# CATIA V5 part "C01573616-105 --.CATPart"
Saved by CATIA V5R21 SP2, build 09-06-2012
Part number: C01573616-105
Revision: ---
Description: PROPRIETARY NOTICE (do not delete / modify)  ***************************************************************************************************  LA SOCIETE EN COMMANDITE  AIRBUS CANADA  ("AIRBUS CANADA")  PAR  L'INTERMEDIAIRE  DE  SES  DIVISIONS  ET/OU  FILIALES  CORPORATIVES,  FOURNIT  LES PRESENTES  INFORMATIONS  AU  GOUVERNEMENT  A  TITRE CONFIDENTIEL. CES  INFORMATIONS ONT UNE TENEUR CONFIDENTIELLE,  AVEC DROITS DE PROPRIETE,  ET NOUS LES CONSIDERONS  EXCLUS  DE   L'APPLICATION  DE  LA LOI SUR L'ACCES A L'INFORMATION  (CANADA),  LES  LOIS  SUR  L'ACCES  A  L'INFORMATION  EUROPEENNES,  LE FREEDOM OF INFORMATION ACT (ETATS-UNIS) ET D'AUTRES LOIS SEMBLABLES. ELLES  PEUVENT  AUSSI  CONSTITUER DES SECRETS INDUSTRIELS DE NOTRE SOCIETE OU DE TIERCES PARTIES. LA DIVULGATION  PUBLIQUE  DE CES  INFORMATIONS NUIRAIT A AIRBUS CANADA OU A DES TIERCES PARTIES.  CES INFORMATIONS PEUVENT EGALEMENT CONTENIR  DES DONNEES QUI SONT CONTROLEE PAR DES LOIS DE CONTROLE DES EXPORTATIONS DU CANADA, L’EUROPE OU LES  ETATS-  UNIS. TOUTE EXPORTATION OU REEXPORTATION DE DONNEES CONTROLEES SANS AUTORISATION EST STRICTEMENT INTERDITE.  TOUTE INTENTION DE LES DIVULGUER EN TOUT OU EN PARTIE DEVRA ETRE SIGNIFIEE A L'AVANCE ET PAR ECRIT AU VICE-  PRESIDENT, SERVICES JURIDIQUES ET CONFORMITE ET SECRETAIRE CORPORATIF D'AIRBUS CANADA.    AIRBUS CANADA LIMITED PARTNERSHIP  ("AIRBUS CANADA"),  BY ITS AFFILIATES AND/OR SUBSIDIARIES, PROVIDES THIS  INFORMATION TO THE GOVERNMENT IN CONFIDENCE. THIS IS PROPRIETARY CONFIDENTIAL INFORMATION WHICH WE CONSIDER  EXCLUDED  FROM  THE  APPLICATION OF THE ACCESS TO INFORMATION ACT (CANADA),  THE FREEDOM OF INFORMATION ACT  (U.S.A.),  THE ACCESS TO INFORMATION LAWS IN EUROPE, AND OTHER SIMILAR LEGISLATION. AND MAY ALSO CONSTITUTE  TRADE SECRETS OF OUR  COMPANY OR THIRD PARTIES.  PUBLIC  RELEASE  OF  THIS INFORMATION  WOULD BE HARMFUL TO  AIRBUS CANADA OR THIRD PARTIES.  THIS  INFORMATION  MAY  ALSO  CONTAIN DATA THAT IS CONTROLLED BY CANADIAN,  EUROPEAN, OR U.S.A. EXPORT CONTROL LAWS. ANY UNAUTHORIZED EXPORT OR RE-EXPORT OF ANY EXPORT CONTROLLED DATA  IS STRICTLY PROHIBITED  ANY INTENTION TO DISCLOSE SUCH INFORMATION,  OR  PART THEREOF,  MUST BE NOTIFIED IN  ADVANCE AND IN WRITING TO THE VICE PRESIDENT, LEGAL AND COMPLIANCE AND CORPORATE SECRETARY OF AIRBUS CANADA.        LES RENSEIGNEMENTS,  LES DONNEES  ET  DESSINS  TECHNIQUES  DIVULGUES  DANS  LES PRESENTES SONT LA PROPRIETE  EXCLUSIVE DE LA SOCIETE EN COMMANDITE AIRBUS CANADA ("AIRBUS CANADA") OU COMPORTENT DES DROITS DE PROPRIETE  APPARTENANT  A  AUTRUI ET NE PEUVENT ETRE DIVULGUES  A  QUICONQUE  NI  UTILISES PAR QUI QUE CE SOIT SANS LE  CONSENTEMENT  ECRIT  D’AIRBUS  CANADA.  LE DETENTEUR DES  PRESENTES  S'ENGAGE, DANS TOUTES CIRCONSTANCES, A  GARDER CONFIDENTIELS LES DONNEES ET DESSINS TECHNIQUES QU'ELLES CONTIENNENT.   CE QUI PRECEDE NE S'APPLIQUE  PAS  AUX PERSONNES  QUI  ONT DES DROITS DE PROPRIETE SUR CES RENSEIGNEMENTS,  DONNEES TECHNIQUES ET DESSINS  DANS LA MESURE OU CES DROITS EXISTENT.    THE INFORMATION,  TECHNICAL DATA  AND  DESIGNS DISCLOSED HEREIN ARE THE EXCLUSIVE PROPERTY OF AIRBUS CANADA  LIMITED PARTNERSHIP  ("AIRBUS CANADA")  OR  CONTAIN PROPRIETARY RIGHTS OF OTHERS  AND ARE NOT TO BE USED OR  DISCLOSED  TO  OTHERS WITHOUT THE WRITTEN CONSENT OF AIRBUS CANADA.  THE RECIPIENT OF THIS DOCUMENT, BY ITS  RETENTION  AND  USE  AGREES TO  HOLD  IN  CONFIDENCE  THE  TECHNICAL DATA AND DESIGNS CONTAINED HEREIN. THE  FOREGOING SHALL NOT APPLY TO PERSONS HAVING PROPRIETARY RIGHTS TO SUCH INFORMATION,  TECHNICAL DATA OR SUCH  DESIGNS TO THE EXTENT THAT SUCH RIGHTS EXIST.    Copyright 2020 Airbus Canada Limited Partnership. All Rights Reserved.  ***********************************
Property "Title": "CRANK, CAM SHAFT, OWE"
Property "Dataset Type": "DETAIL"
Property "Supplier Name And CAGE Code": "AIRBUS CANADA LIMITED PARTNERSHIP L0J48"
Property "Major Supplier Code": "LP"
Property "3D Only": "N/A"
Property "Material Form": "BAR - ROUND"
Property "Finish Code": "T002"
Property "PCCN": "2"
Property "Organization": "DESIGN"
Property "Design Authority Program": "BD-500"
Property "Color Coded": "N/A"
Property "Thickness": 0
Property "Inside Diameter": 0
Property "Outside Diameter": 3.25
Property "Length": 0
Property "Width": 0
Property "Wall": 0
Property "Wire Gauge": "-"
Property "Alloy": "6AL-4V"
Property "Final Condition": "ANL"
Property "Density": "N/A"
Property "Form": "N/A"
Property "Grade/Composition": "N/A"
Property "Material Class": "N/A"
Property "Mesh Cell Size": "N/A"
Property "Standard Spec Die": "N/A"
Property "Type": "N/A"
Property "Style": "N/A"
Property "MFG Process": "MACHINED"
Property "Material Specification Production": "AMS4928"
Property "Material Description Production": "TITANIUM"
Property "Dimensions": "DIMENSIONS ARE IN INCHES"
Property "Roughness": "ALL MACHINED SURFACES 125 Ra MAX"
Property "Eng. Tolerances": "LINEAR .XX= +/-.03; .XXX= +/-.010; ANGULAR= +/-0.5 DEG"
Property "Tool Design Tolerances": "LINEAR .X= +/-.06; .XX= +/-.015; .XXX= +/-.005; .XXXX= +/-.001; ANGULAR= +/-0.5 DEG"
Property "Project": "BA"
Publications: "PartBody", "DATUM_A", "DATUM_C", "DATUM_B"
Material "TI-6AL-4V": density 4428.78 kg/m3, Young's modulus 1.11695e+11 Pa, Poisson ratio 0.31
Bounding box of the stored display mesh (mm): x -37.389 to 76.2, y -36.336 to 20.458, z -20.458 to 61.276
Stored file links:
  C:\Users\CQQZ006\Desktop\A220钢钛件\舱门\C01573616-105\C01573616-105 --.CATPart

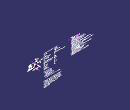
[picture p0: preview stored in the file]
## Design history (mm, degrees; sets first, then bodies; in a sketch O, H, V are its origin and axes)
AxisSystem1 "Absolute Axis System": origin (0, 0, 0), X (1, 0, 0), Y (0, 1, 0), Z (0, 0, 1)
Part_3D_Annotations1 "CATTPSSet"
Set1 "Pilot_Holes"
  Set2 "3/16\""
    Line1: type Normal, RefPoint Point3, RefSkin Plane3, Start 22.86, End -22.86
    Line2: type Normal, RefPoint Point4, RefSkin Plane2, Start 22.86, End -22.86
    Point1: type OnCurve, Support Line1, RefPoint Point3, Length 9.144
    Point2: type OnCurve, Support Line2, RefPoint Point4, Length 9.144
Set3 "Geometrical Set for 3D Annotations"
  Set4 "No Show Geometry"
    Extract1 "DATUM_A": ExtractElem face of Shaft1 from Sketch1.L3
    Extract2 "DATUM_C": ExtractElem face of Shaft1 from Sketch1.L4
    Extract3 "DATUM_B": ExtractElem face of Hole1
  Set5 "Surfaces for 3D Annotations"
    Set6 "CHANGE 2"
      DatumSurface1
    Set7 "CHANGE 1"
      DatumSurface2
Set8 "Construction_Geometry"
  Plane1: type Angle, RefPlane zx-plane, Direction X axis, Angle 31.5
  Plane2: type Angle, RefPlane zx-plane, Direction X axis, Angle 63.5
  Plane3: type Angle, RefPlane Plane2, Direction X axis, Angle 90
  Point3: (55.88, 0, 0), in AxisSystem1
  Point4: (68.58, 0, 0), in AxisSystem1
Body1 "PartBody" (main body)
  Sketch1 on zx-plane, origin (0, 0, 0), H (-1, 0, 0), V (0, 0, 1)
    line L1 (-76.2, 7.1158) -> (-76.2, 9.144)
    line L2 (-76.2, 9.144) -> (-41.9383, 9.144)
    line L3 (-40.64, 9.5009) -> (3.048, 9.5009)
    line L4 (3.81, 10.2629) -> (3.81, 44.45)
    line L5 (21.7678, 50.8) -> (21.7678, 78.74)
    line L6 (21.7678, 78.74) -> (37.3888, 78.74)
    line L7 (37.3888, 78.74) -> (37.3888, 12.7)
    line L8 (37.3888, 12.7) -> (12.7, 12.7)
    arc A1 centre (12.7, 10.16) radius 2.54 from (12.7, 12.7) to (10.16, 10.16) ccw
    line L9 (10.16, 10.16) -> (10.16, 6.604)
    line L10 (-38.1, 7.1158) -> (-76.2, 7.1158)
    axis line L11 (-107.0731, 0) -> (83.8961, 0)
    point P8 (-107.0731, 0)
    arc A2 centre (-41.9383, 11.684) radius 2.54 from (-41.9383, 9.144) to (-40.64, 9.5009) ccw
    point P12 (-40.64, 9.5009)
    line L12 (10.16, 6.604) -> (-36.1899, 6.604)
    line L13 (-36.1899, 6.604) -> (-38.1, 7.1158)
    point P14 (-38.1, 7.1158)
    arc A3 centre (3.048, 10.2629) radius 0.762 from (3.048, 9.5009) to (3.81, 10.2629) ccw
    arc A4 centre (15.4178, 50.8) radius 6.35 from (15.4178, 44.45) to (21.7678, 50.8) ccw
    point P18 (15.4178, 50.8)
    line L14 (3.81, 44.45) -> (15.4178, 44.45)
    distance L11 L10 = 7.1158
    distance L2 L11 = 9.144
    distance L3 L11 = 9.5009
    distance L4 V = 3.81
    radius A1 = 2.54
    distance L8 L11 = 12.7
    distance L4 P12 = 44.45
    radius A2 = 2.54
    distance L12 L11 = 6.604
    radius A3 = 0.762
    radius A4 = 6.35
    distance P18 L11 = 50.8
    distance L11 L6 = 78.74
    angle L13 L10 = 15
    distance L5 L7 = 15.621
    distance L1 L4 = 80.01
    distance P14 L1 = 38.1
    distance L4 L5 = 17.9578
    distance L4 L9 = 6.35
    vertical: L1 V, L4 V, L7 V, L5 V, L9 V
    horizontal: L2 H, L3 H, L6 H, L8 H, L10 H, L11 H, L12 H, L14 H
    tangency: A1 L8, L9 A1, A2 L2, A3 L3, A3 L4, A4 L5, A4 L14
    coincidence: P8 H
  Shaft1: profile Sketch1, axis Sketch1.L11, angle 360
  Body2
    Sketch2 on yz-plane, origin (0, 0, 0), H (0, 1, 0), V (0, 0, 1)
      construction line L1 (0, 0) -> (0, 53.34)
      arc A1 centre (0, 53.34) radius 7.9375 from (7.3065, 50.2386) to (-6.7314, 57.5462) ccw
      circle A2 centre (0, 53.34) radius 3.1756
      arc A3 centre (0, 0) radius 15.24 from (-14.4097, -4.9617) to (13.0632, 7.8492) ccw
      line L2 (13.0632, 7.8492) -> (1.4784, 27.1296)
      arc A4 centre (9.0986, 31.7083) radius 8.89 from (0.9153, 35.1819) to (1.4784, 27.1296) ccw
      line L3 (-6.7314, 57.5462) -> (-22.3484, 32.5538)
      arc A5 centre (-11.5782, 25.8238) radius 12.7 from (-22.3484, 32.5538) to (-23.5863, 21.6891) ccw
      line L4 (-23.5863, 21.6891) -> (-14.4097, -4.9617)
      line L5 (7.3065, 50.2386) -> (0.9153, 35.1819)
      circle A6 centre (0, 0) radius 81.28
      radius A1 = 7.9375
      length L1 = 53.34
      radius A2 = 3.1756
      radius A3 = 15.24
      radius A4 = 8.89
      angle L1 L2 = 31
      radius A5 = 12.7
      angle L3 L5 = 9
      angle L4 L1 = 19
      angle L5 L1 = 23
      radius A6 = 81.28
      tangency: L2 A3, L2 A4, L3 A1, A5 L3, A5 L4, A3 L4, L5 A1, A4 L5
      vertical: L1 V
    Pocket1: profile Sketch2, direction (-1, 0, 0), length 127, opposite side length -24.892, outer side
    Fillet1: radius 2.286, on edge [start face of Pocket1 | face of Pocket1 from Sketch2.L2]
  Assemble1: tool Body2
  Body3
    Sketch3 on YZ plane of AxisSystem1, origin (0, 0, 0), H (0, -1, 0), V (0, 0, 1)
      point P1 (0, 53.34)
      line L1 (54.3233, 78.74) -> (-25.4, 11.8442)
      line L2 (-25.4, 11.8442) -> (-25.4, 78.74)
      line L3 (-25.4, 78.74) -> (54.3233, 78.74)
      reference projected point E1 (0, 53.34) from axis of face of Pocket1 from Sketch2.A1
      construction line L4 (0, 53.34) -> (0, 0)
      angle L1 L4 = 50
      distance L1 O = 25.4
      distance L3 P1 = 25.4
      distance L2 P1 = 25.4
      coincidence: P1 E1
      vertical: L4 V, L2 V
      horizontal: L3 H
    Pocket2: profile Sketch3, direction (-1, 0, 0), up to face of Shaft1 from Sketch1.L5, offset -3.048, opposite side up to face of Shaft1 from Sketch1.L7, offset -3.048
    Fillet2: radius 2.286, on edge [face of Pocket2 from Sketch3.L1 | start face of Pocket2]; edge [end face of Pocket2 | face of Pocket2 from Sketch3.L1]
  Assemble2: tool Body3
  Body4
    Sketch4 on Plane1, origin (0, 0, 0), H (-1, 0, 0), V (0, -0.5225, 0.8526)
      line L1 (63.5, 59.8462) -> (3.81, -25.4)
      line L2 (3.81, -25.4) -> (63.5, -25.4)
      line L3 (63.5, -25.4) -> (63.5, 59.8462)
      reference intersected line E1 through (0, 0) direction (-1, 0) from xy-plane
      point P3 (3.81, -25.4)
      reference intersected line E2 through (0, 0) direction (0, -1) from yz-plane
      distance E1 L2 = 25.4
      distance E2 P3 = 3.81
      angle L1 H = 55
      distance L3 V = 63.5
      horizontal: L2 H
      vertical: L3 V
    Pocket3: profile Sketch4, direction (0, -0.8526, -0.5225), length 50.8, mirrored extent
  Assemble3: tool Body4
  Body5
    Sketch5 on yz-plane, origin (0, 0, 0), H (0, 1, 0), V (0, 0, 1)
      line L1 (-4.1125, 33.2924) -> (-8.8837, 37.296)
      point P1 (15.9514, 16.4568)
      projected line E1 (-24.3023, 23.7685) -> (-17.2232, 3.2093) from Sketch2.L4
      projected circle E3 centre (0, 0) radius 12.7 from edge [face of Pocket3 from Sketch4.L1 | face of Shaft1 from Sketch1.L8]
      projected arc E4 centre (0, 0) radius 12.7 from (-12.0081, -4.1347) to (10.886, 6.541) cw from edge [face of Pocket3 from Sketch4.L1 | face of Shaft1 from Sketch1.L8]
      projected line E5 (8.8882, 14.7976) -> (1.4784, 27.1296) from edge [face of Pocket3 from Sketch4.L1 | face of Pocket1 from Sketch2.L2]
      projected arc E6 centre (-11.5782, 25.8238) radius 12.7 from (-23.5863, 21.6891) to (-22.3484, 32.5538) cw from edge [face of Pocket1 from Sketch2.A5 | face of Shaft1 from Sketch1.L7]
      offset line E7 (-21.1847, 22.516) -> (-13.5669, 0.3923) from face of Pocket1 from Sketch2.L4
      offset line E8 (-21.1847, 22.516) -> (-12.0081, -4.1347) from face of Pocket1 from Sketch2.L4
      reference projected line E9 (-14.4147, 45.2527) -> (0.2918, 32.9125) from edge [face of Fillet2 | face of Pocket2 from Sketch3.L1]
      offset arc E11 centre (-11.5782, 25.8238) radius 10.16 from (-21.1847, 22.516) to (-20.1944, 31.2078) cw from edge [face of Pocket1 from Sketch2.A5 | face of Shaft1 from Sketch1.L7]
      offset arc E12 centre (-11.5782, 25.8238) radius 10.16 from (-21.1847, 22.516) to (-20.1944, 31.2078) cw from edge [face of Pocket1 from Sketch2.A5 | face of Shaft1 from Sketch1.L7]
      offset line E13 (-4.5773, 56.2002) -> (-20.1944, 31.2078) from face of Pocket1 from Sketch2.L3
      offset line E14 (-17.2145, 35.9765) -> (-20.1944, 31.2078) from face of Pocket1 from Sketch2.L3
      offset arc E15 centre (9.0986, 31.7083) radius 11.43 from (-1.4228, 36.1743) to (-0.6988, 25.8214) ccw from Sketch2.A4
      offset arc E16 centre (9.0986, 31.7083) radius 11.43 from (-2.187, 29.8972) to (-0.6988, 25.8214) ccw from Sketch2.A4
      point P20 (-0.6988, 25.8214)
      line L2 (-0.6988, 25.8214) -> (10.886, 6.541)
      arc A1 centre (-7.7044, 29.0118) radius 5.588 from (-2.187, 29.8972) to (-4.1125, 33.2924) ccw
      arc A2 centre (-12.4756, 33.0153) radius 5.588 from (-8.8837, 37.296) to (-17.2145, 35.9765) ccw
      distance E9 L1 = 2.54
      radius A1 = 5.588
      radius A2 = 5.588
      coincidence: L1 P1, P20 L2
      tangency: L2 E3, E15 L2, A1 E15, A1 L1, A2 L1, A2 E13
    Pocket4: profile Sketch5, direction (-1, 0, 0), length 38.1, opposite side up to face of Shaft1 from Sketch1.L5, offset -3.048
  Assemble4: tool Body5
  Fillet3: radius 2.286, on edge [start face of Pocket4 | face of Pocket4 from Sketch5.E8]
  Sketch6 on face of Shaft1 from Sketch1.L7, origin (-37.3888, 0, 0), H (0, -1, 0), V (0, 0, 1)
    point P1 (0, 53.34)
    reference projected circle E1 centre (0, 53.34) radius 3.1756 from Sketch2.A2
    concentricity: E1 P1
  Hole1: placed by Sketch6, at (-37.3888, 0, 53.34) direction (1, 0, 0), diameter 9.5364, through (limit type 6)
  Body6
    Sketch7 on start face of Pocket1, origin (-24.892, 0, 0), H (0, 1, 0), V (0, 0, 1)
      arc A1 centre (0, 0) radius 15.24 from (-14.4097, -4.9617) to (15.0268, 2.54) ccw
      circle A2 centre (0, 0) radius 76.2
      construction circle A3 centre (61.2423, 37.6923) radius 3.9827
      point P1 (61.2423, 37.6923)
      line L1 (-19.6825, 29.0498) -> (-23.0944, 27.04)
      line L2 (-13.7166, 17.8245) -> (-23.0944, 27.04)
      point P2 (-23.0944, 27.04)
      construction line L3 (0, 0) -> (-34.2785, 40.135)
      point P5 (61.2423, 37.6923)
      construction line L4 through (-3.408, 30.4585) direction (-0.9938, -0.1112)
      construction line L5 (0, 0) -> (0, 53.34)
      construction line L6 (-31.6295, 0) -> (0, 0)
      arc A4 centre (-15.0268, -2.54) radius 30.48 from (15.0268, 2.54) to (-2.0456, 25.0375) ccw
      point P9 (-15.0268, -2.54)
      arc A5 centre (-15.1705, 21.3899) radius 8.89 from (-11.3843, 29.4334) to (-19.6825, 29.0498) ccw
      point P10 (-15.1705, 21.3899)
      line L7 (-11.3843, 29.4334) -> (-2.0456, 25.0375)
      line L8 (-33.7076, 23.7362) -> (-29.2865, 15.4213)
      line L9 (-36.3364, 22.1878) -> (-29.7925, 9.8805)
      line L10 (-21.5165, 13.23) -> (-13.7166, 17.8245)
      point P15 (-6.7924, 21.9031)
      line L11 (-36.3364, 22.1878) -> (-33.7076, 23.7362)
      point P16 (-14.5273, 35.0343)
      construction line L12 (-6.7924, 21.9031) -> (-14.5273, 35.0343)
      arc A6 centre (-24.3526, 18.0447) radius 5.588 from (-29.2865, 15.4213) to (-21.5165, 13.23) ccw
      line L13 (-29.7925, 9.8805) -> (-21.0345, 7.2029)
      projected line E2 (-23.5863, 21.6891) -> (-14.4097, -4.9617) from Sketch2.L4
      projected line E3 (-17.3847, 3.6783) -> (-14.4097, -4.9617) from Sketch2.L4
      point P22 (-23.5863, 21.6891)
      arc A7 centre (-22.6682, 1.859) radius 5.588 from (-21.0345, 7.2029) to (-17.3847, 3.6783) cw
      radius A1 = 15.24
      radius A2 = 76.2
      radius A3 = 3.9827
      distance O P2 = 35.56
      angle L5 L3 = 40.5
      angle L2 L3 = 5
      angle L1 L3 = 80
      distance P9 L6 = 2.54
      radius A4 = 30.48
      distance P10 L2 = 1.524
      radius A5 = 8.89
      distance L8 L9 = 3.048
      angle L8 L5 = 28
      distance L8 P2 = 10.922
      distance L10 L1 = 12.7
      distance L10 L11 = 15.24
      radius A6 = 5.588
      angle L13 L9 = 45
      distance A6 L13 = 3.81
      radius A7 = 5.588
      coincidence: P2 L1, P2 L2, P5 P1, P2 L3, L10 P15, P16 L11, E2 P22
      fix: P5, L4
      perpendicularity: L6 L5, L12 L10, L12 L11
      tangency: A4 A1, A5 L1, L7 A5, L7 A4, A6 L8, A6 L10, A7 L13, A7 E2
    Pocket5: profile Sketch7, direction (-1, 0, 0), up to face of Shaft1 from Sketch1.L5, opposite side length 50.8
    Fillet4: radius 0.508, on edge [face of Pocket5 from Sketch7.L2 | face of Pocket5 from Sketch7.L1]
    Fillet5: radius 5.588, on edge [face of Pocket5 from Sketch7.L10 | face of Pocket5 from Sketch7.L2]
    Fillet6: radius 2.286, on edge [end face of Pocket5 | face of Fillet5]; edge [start face of Pocket5 | face of Pocket5 from Sketch7.A1]
  Assemble5: tool Body6
  Sketch8 on face of Shaft1 from Sketch1.L4, origin (-3.81, 0, 0), H (0, 1, 0), V (0, 0, 1)
    circle A1 centre (0, 0) radius 17.78
    circle A2 centre (0, 0) radius 44.9636
    radius A2 = 44.9636
    radius A1 = 17.78
  Pocket6: profile Sketch8, direction (-1, 0, 0), length 4.826
  Fillet7: radius 2.286, on edge [end face of Pocket6 | face of Pocket6 from Sketch8.A1]
  Body7
    Sketch9 on YZ plane of AxisSystem1, origin (0, 0, 0), H (0, -1, 0), V (0, 0, 1)
      offset line E2 (17.4865, 24.3781) -> (21.1979, 28.0253) from face of Pocket5 from Sketch7.L2
      offset line E3 (11.6544, 18.6469) -> (12.5962, 19.5725) from face of Pocket5 from Sketch7.L2
      arc A1 centre (0, 0) radius 12.7 from (-10.886, 6.541) to (11.161, 6.0599) ccw
      point P5 (0, 0)
      line L1 (11.161, 6.0599) -> (10.0728, 8.0642)
      reference projected line E4 (2.0456, 25.0375) -> (11.3843, 29.4334) from Sketch7.L7
      line L2 (8.3031, 25.7371) -> (-1.3237, 21.2057)
      reference projected line E5 (-13.0632, 7.8492) -> (-1.4784, 27.1296) from Sketch2.L2
      line L3 (-2.9668, 19.7208) -> (-10.886, 6.541)
      arc A2 centre (0.299, 17.7585) radius 3.81 from (-1.3237, 21.2057) to (-2.9668, 19.7208) ccw
      arc A3 centre (17.8854, 12.3061) radius 8.89 from (10.0728, 8.0642) to (11.6544, 18.6469) cw
      arc A4 centre (9.9258, 22.29) radius 3.81 from (12.5962, 19.5725) to (8.3031, 25.7371) ccw
      radius A1 = 12.7
      distance L2 E4 = 2.032
      radius A2 = 3.81
      radius A3 = 8.89
      radius A4 = 3.81
      angle L1 V = 28.5
      coincidence: P5 O
      tangency: L1 A1, A2 L2, A2 L3, L3 A1, A3 L1, A3 E2, A4 L2, A4 E2
      parallelism: L3 E5
    Pocket7: profile Sketch9, direction (-1, 0, 0), length 33.02, opposite side length -6.858
    Sketch10 on start face of Pocket7, origin (-6.858, 0, 0), H (0, 1, 0), V (0, 0, 1)
      circle A1 centre (0, 0) radius 12.7
      reference projected arc E1 centre (0, 0) radius 12.7 from (-11.161, 6.0599) to (10.886, 6.541) ccw
      circle A2 centre (0, 0) radius 31.9975
      radius A2 = 31.9975
      coincidence: A1 E1
    Pad1: profile Sketch10, direction (-1, 0, 0), length 4.826
    Fillet8: radius 2.286, on start face of Pocket7; edge [face of Pocket7 from Sketch9.A4 | end face of Pad1]
  Assemble6: tool Body7
  Chamfer1: length 1.016, second length 1.016, on edge [face of Shaft1 from Sketch1.L10 | face of Shaft1 from Sketch1.L1]
  Chamfer2: length 1.016, second length 1.016, on edge [start face of Pocket7 | face of Shaft1 from Sketch1.L12]
  Body8
    Sketch11 on yz-plane, origin (0, 0, 0), H (0, 1, 0), V (0, 0, 1)
      projected line E1 (-36.3364, 22.1878) -> (-29.7925, 9.8805) from Sketch7.L9
      point P1 (-36.3364, 22.1878)
      projected line E2 (-29.7925, 9.8805) -> (-21.0345, 7.2029) from Sketch7.L13
      projected arc E3 centre (-22.6682, 1.859) radius 5.588 from (-17.3847, 3.6783) to (-21.0345, 7.2029) ccw from Sketch7.A7
      projected line E4 (-17.3847, 3.6783) -> (-14.4097, -4.9617) from Sketch7.E3
      point P8 (-14.4097, -4.9617)
      projected arc E5 centre (0, 0) radius 15.24 from (-14.4097, -4.9617) to (15.0268, 2.54) ccw from Sketch7.A1
      projected arc E6 centre (0, 0) radius 15.24 from (-14.4097, -4.9617) to (15.0268, 2.54) ccw from Sketch7.A1
      point P9 (-14.4097, -4.9617)
      projected line E7 (-6.7314, 57.5462) -> (-22.3484, 32.5538) from Sketch2.L3
      projected line E8 (-6.7314, 57.5462) -> (-23.7265, 30.3484) from Sketch2.L3
      point P12 (-22.3484, 32.5538)
      projected line E9 (-33.7076, 23.7362) -> (-36.3364, 22.1878) from Sketch7.L11
      projected line E10 (-25.6293, 28.4948) -> (-36.3364, 22.1878) from Sketch7.L11
      point P13 (-33.7076, 23.7362)
      point P14 (-36.3364, 22.1878)
      arc A1 centre (-28.4654, 33.3096) radius 5.588 from (-25.6293, 28.4948) to (-23.7265, 30.3484) ccw
      circle A2 centre (0, 0) radius 127
      projected arc E11 centre (0, 53.34) radius 7.9375 from (7.3065, 50.2386) to (-6.7314, 57.5462) ccw from Sketch2.A1
      projected arc E12 centre (0, 53.34) radius 7.9375 from (7.3065, 50.2386) to (-6.7314, 57.5462) ccw from Sketch2.A1
      projected circle E13 centre (0, 53.34) radius 3.1756 from Sketch2.A2
      projected line E14 (0.9153, 35.1819) -> (7.3065, 50.2386) from Sketch2.L5
      projected arc E15 centre (9.0986, 31.7083) radius 8.89 from (0.9153, 35.1819) to (1.4784, 27.1296) ccw from Sketch2.A4
      projected line E16 (13.0632, 7.8492) -> (1.4784, 27.1296) from Sketch2.L2
      projected line E17 (5.7462, 20.0268) -> (1.4784, 27.1296) from Sketch2.L2
      projected arc E18 centre (-15.0268, -2.54) radius 30.48 from (15.0268, 2.54) to (-2.0456, 25.0375) ccw from Sketch7.A4
      projected arc E19 centre (-15.0268, -2.54) radius 30.48 from (15.0268, 2.54) to (6.5756, 18.9627) ccw from Sketch7.A4
      arc A3 centre (10.536, 22.9049) radius 5.588 from (6.5756, 18.9627) to (5.7462, 20.0268) cw
      radius A1 = 5.588
      radius A2 = 127
      radius A3 = 5.588
      coincidence: E9 P13, E7 P12, P1 P14, P8 P9
      tangency: A1 E9, A1 E7, A3 E18, A3 E16
    Pocket8: profile Sketch11, direction (-1, 0, 0), length 127, mirrored extent
  Assemble7: tool Body8
  Fillet9: radius 2.286, on edge [end face of Pocket6 | face of Pocket8 from Sketch11.E10]
  Body9
    Sketch12 on yz-plane, origin (0, 0, 0), H (0, 1, 0), V (0, 0, 1)
      construction line L1 (0, 0) -> (0, 53.34)
      point P1 (0, 53.34)
      arc A1 centre (0, 53.34) radius 7.9375 from (7.3065, 50.2386) to (0, 61.2775) ccw
      arc A2 centre (0, 0) radius 15.24 from (0, -15.24) to (13.0632, 7.8492) ccw
      line L2 (13.0632, 7.8492) -> (1.4784, 27.1296)
      arc A3 centre (9.0986, 31.7083) radius 8.89 from (0.9153, 35.1819) to (1.4784, 27.1296) ccw
      line L3 (7.3065, 50.2386) -> (0.9153, 35.1819)
      arc A4 centre (0, 0) radius 81.28 from (0, -81.28) to (0, 81.28) ccw
      line L4 (0, 81.28) -> (0, 61.2775)
      line L5 (0, -15.24) -> (0, -81.28)
      radius A1 = 7.9375
      length L1 = 53.34
      radius A2 = 15.24
      radius A3 = 8.89
      angle L1 L2 = 31
      angle L3 L1 = 23
      radius A4 = 81.28
      tangency: L2 A2, L2 A3, L3 A1, A3 L3
      vertical: L1 V, L4 V, L5 V
      coincidence: O L4, L4 L5, P1 L4, O L5
    Pocket9: profile Sketch12, direction (-1, 0, 0), length 127, opposite side length -17.78
    Fillet10: radius 2.286, on edge [start face of Pocket9 | face of Pocket9 from Sketch12.A2]
  Assemble8: tool Body9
